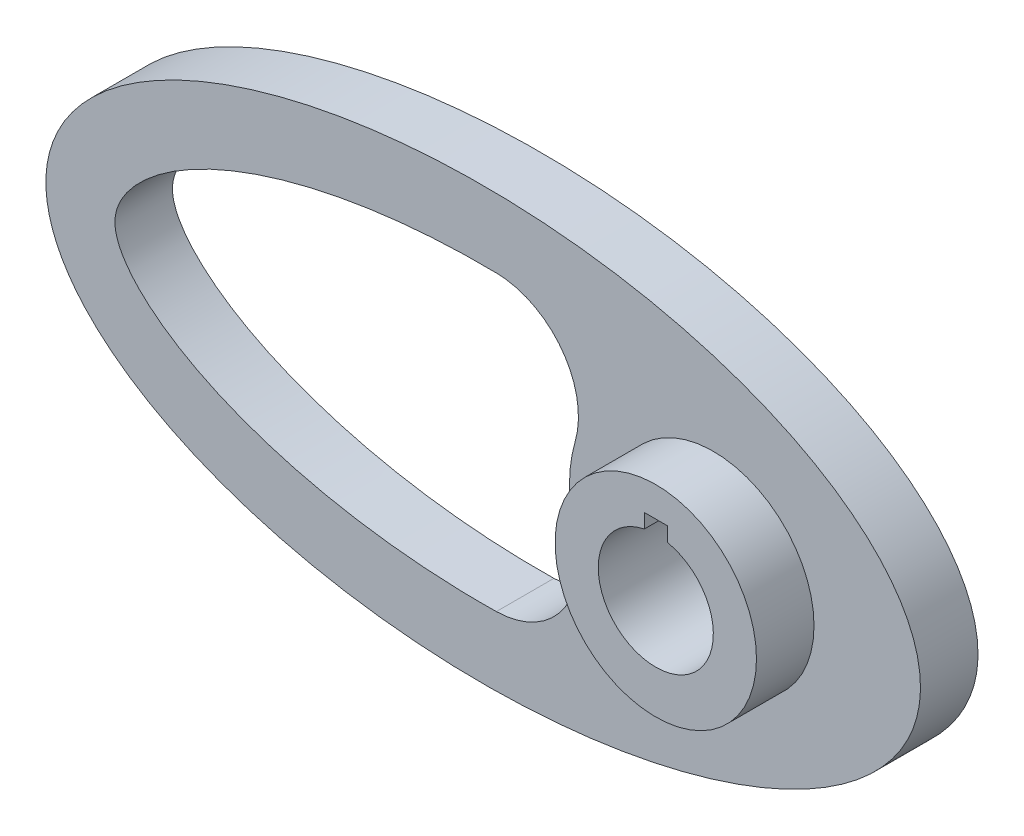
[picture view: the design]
ISO-10303-21;
HEADER;
FILE_DESCRIPTION(('STEP AP214'),'2;1');
FILE_NAME('part.step','',(''),(''),'','','');
FILE_SCHEMA(('AUTOMOTIVE_DESIGN { 1 0 10303 214 1 1 1 1 }'));
ENDSEC;
DATA;
#1=APPLICATION_CONTEXT('core data for automotive mechanical design processes');
#2=APPLICATION_PROTOCOL_DEFINITION('international standard','automotive_design',2000,#1);
#3=PRODUCT_CONTEXT('',#1,'mechanical');
#4=PRODUCT('Part','Part','',(#3));
#5=PRODUCT_RELATED_PRODUCT_CATEGORY('part','',(#4));
#6=PRODUCT_DEFINITION_FORMATION('','',#4);
#7=PRODUCT_DEFINITION_CONTEXT('part definition',#1,'design');
#8=PRODUCT_DEFINITION('design','',#6,#7);
#9=PRODUCT_DEFINITION_SHAPE('','',#8);
#10=(LENGTH_UNIT() NAMED_UNIT(*) SI_UNIT(.MILLI.,.METRE.));
#11=(NAMED_UNIT(*) PLANE_ANGLE_UNIT() SI_UNIT($,.RADIAN.));
#12=(NAMED_UNIT(*) SI_UNIT($,.STERADIAN.) SOLID_ANGLE_UNIT());
#13=UNCERTAINTY_MEASURE_WITH_UNIT(LENGTH_MEASURE(1.E-05),#10,'distance_accuracy_value','');
#14=(GEOMETRIC_REPRESENTATION_CONTEXT(3) GLOBAL_UNCERTAINTY_ASSIGNED_CONTEXT((#13)) GLOBAL_UNIT_ASSIGNED_CONTEXT((#10,
#11,#12)) REPRESENTATION_CONTEXT('',''));
#15=CARTESIAN_POINT('',(0.,0.,0.));
#16=DIRECTION('',(0.,0.,1.));
#17=DIRECTION('',(1.,0.,0.));
#18=AXIS2_PLACEMENT_3D('',#15,#16,#17);
#19=CARTESIAN_POINT('',(0.,0.,10.));
#20=DIRECTION('',(0.,0.,1.));
#21=DIRECTION('',(1.,0.,0.));
#22=AXIS2_PLACEMENT_3D('',#19,#20,#21);
#23=PLANE('',#22);
#24=CARTESIAN_POINT('',(2.29138758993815,25.4815579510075,10.));
#25=CARTESIAN_POINT('',(1.04978490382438,25.5014988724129,10.));
#26=CARTESIAN_POINT('',(-0.192085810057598,25.5052866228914,10.));
#27=CARTESIAN_POINT('',(-2.67421151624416,25.480297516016,10.));
#28=CARTESIAN_POINT('',(-3.9144668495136,25.4515543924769,10.));
#29=CARTESIAN_POINT('',(-6.39335454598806,25.3613033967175,10.));
#30=CARTESIAN_POINT('',(-7.63198732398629,25.2998069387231,10.));
#31=CARTESIAN_POINT('',(-10.1076273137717,25.143877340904,10.));
#32=CARTESIAN_POINT('',(-11.3446337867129,25.0494324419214,10.));
#33=CARTESIAN_POINT('',(-13.8169750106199,24.8266097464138,10.));
#34=CARTESIAN_POINT('',(-15.05230639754,24.6981945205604,10.));
#35=CARTESIAN_POINT('',(-17.521265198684,24.4065386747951,10.));
#36=CARTESIAN_POINT('',(-18.7548847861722,24.2432316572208,10.));
#37=CARTESIAN_POINT('',(-21.2203615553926,23.8802458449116,10.));
#38=CARTESIAN_POINT('',(-22.4522037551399,23.6804649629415,10.));
#39=CARTESIAN_POINT('',(-24.9140463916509,23.2423508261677,10.));
#40=CARTESIAN_POINT('',(-26.1440203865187,23.0038685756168,10.));
#41=CARTESIAN_POINT('',(-28.6014017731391,22.4860832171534,10.));
#42=CARTESIAN_POINT('',(-29.8287700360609,22.2065938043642,10.));
#43=CARTESIAN_POINT('',(-32.2730954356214,21.6051248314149,10.));
#44=CARTESIAN_POINT('',(-33.4900525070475,21.2831450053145,10.));
#45=CARTESIAN_POINT('',(-35.9103508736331,20.5939890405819,10.));
#46=CARTESIAN_POINT('',(-37.1137000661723,20.226840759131,10.));
#47=CARTESIAN_POINT('',(-39.5055771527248,19.4430324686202,10.));
#48=CARTESIAN_POINT('',(-40.6940886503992,19.0263222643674,10.));
#49=CARTESIAN_POINT('',(-43.0502715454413,18.1392862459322,10.));
#50=CARTESIAN_POINT('',(-44.217955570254,17.6689942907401,10.));
#51=CARTESIAN_POINT('',(-45.9481669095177,16.9194711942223,10.));
#52=CARTESIAN_POINT('',(-46.5204844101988,16.6627128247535,10.));
#53=CARTESIAN_POINT('',(-47.6569294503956,16.1336675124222,10.));
#54=CARTESIAN_POINT('',(-48.2210674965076,15.8614032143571,10.));
#55=CARTESIAN_POINT('',(-49.3406149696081,15.3003535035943,10.));
#56=CARTESIAN_POINT('',(-49.8960299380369,15.0115791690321,10.));
#57=CARTESIAN_POINT('',(-50.9972040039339,14.4157350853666,10.));
#58=CARTESIAN_POINT('',(-51.542960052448,14.1086596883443,10.));
#59=CARTESIAN_POINT('',(-52.6240771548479,13.47466429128,10.));
#60=CARTESIAN_POINT('',(-53.1594193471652,13.147712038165,10.));
#61=CARTESIAN_POINT('',(-54.2183300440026,12.4713832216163,10.));
#62=CARTESIAN_POINT('',(-54.7418527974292,12.12193480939,10.));
#63=CARTESIAN_POINT('',(-55.7749364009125,11.3976938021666,10.));
#64=CARTESIAN_POINT('',(-56.2844178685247,11.0227872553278,10.));
#65=CARTESIAN_POINT('',(-57.0337582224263,10.4412930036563,10.));
#66=CARTESIAN_POINT('',(-57.281068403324,10.2442635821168,10.));
#67=CARTESIAN_POINT('',(-57.7697192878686,9.84342837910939,10.));
#68=CARTESIAN_POINT('',(-58.0110660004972,9.63962994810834,10.));
#69=CARTESIAN_POINT('',(-58.4872732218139,9.22468734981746,10.));
#70=CARTESIAN_POINT('',(-58.7221351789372,9.01354484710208,10.));
#71=CARTESIAN_POINT('',(-59.184837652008,8.58330701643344,10.));
#72=CARTESIAN_POINT('',(-59.4126721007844,8.36420515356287,10.));
#73=CARTESIAN_POINT('',(-59.8606924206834,7.91760012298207,10.));
#74=CARTESIAN_POINT('',(-60.080865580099,7.6900841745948,10.));
#75=CARTESIAN_POINT('',(-60.5115641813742,7.22649144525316,10.));
#76=CARTESIAN_POINT('',(-60.7220991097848,6.99042351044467,10.));
#77=CARTESIAN_POINT('',(-61.1313808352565,6.50996293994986,10.));
#78=CARTESIAN_POINT('',(-61.3301732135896,6.26560921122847,10.));
#79=CARTESIAN_POINT('',(-61.7145817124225,5.76789181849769,10.));
#80=CARTESIAN_POINT('',(-61.9002371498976,5.51455876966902,10.));
#81=CARTESIAN_POINT('',(-62.1672003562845,5.12670200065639,10.));
#82=CARTESIAN_POINT('',(-62.2542597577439,4.9961206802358,10.));
#83=CARTESIAN_POINT('',(-62.4242991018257,4.73213028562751,10.));
#84=CARTESIAN_POINT('',(-62.5072747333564,4.59871842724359,10.));
#85=CARTESIAN_POINT('',(-62.6688983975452,4.32889217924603,10.));
#86=CARTESIAN_POINT('',(-62.7475364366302,4.1924717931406,10.));
#87=CARTESIAN_POINT('',(-62.8999829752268,3.91627986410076,10.));
#88=CARTESIAN_POINT('',(-62.9737721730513,3.77649763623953,10.));
#89=CARTESIAN_POINT('',(-63.116028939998,3.49327587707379,10.));
#90=CARTESIAN_POINT('',(-63.1844648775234,3.34982041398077,10.));
#91=CARTESIAN_POINT('',(-63.3150602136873,3.05961797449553,10.));
#92=CARTESIAN_POINT('',(-63.3772027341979,2.91286337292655,10.));
#93=CARTESIAN_POINT('',(-63.4940909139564,2.61689388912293,10.));
#94=CARTESIAN_POINT('',(-63.5488564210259,2.46768687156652,10.));
#95=CARTESIAN_POINT('',(-63.6500699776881,2.16719850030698,10.));
#96=CARTESIAN_POINT('',(-63.6965543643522,2.01592951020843,10.));
#97=CARTESIAN_POINT('',(-63.7595502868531,1.78723887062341,10.));
#98=CARTESIAN_POINT('',(-63.779422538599,1.7107324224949,10.));
#99=CARTESIAN_POINT('',(-63.8168217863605,1.55708383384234,10.));
#100=CARTESIAN_POINT('',(-63.8343469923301,1.4799412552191,10.));
#101=CARTESIAN_POINT('',(-63.8669622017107,1.32499797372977,10.));
#102=CARTESIAN_POINT('',(-63.8820477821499,1.24719633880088,10.));
#103=CARTESIAN_POINT('',(-63.9096542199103,1.09086592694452,10.));
#104=CARTESIAN_POINT('',(-63.9221662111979,1.01233557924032,10.));
#105=CARTESIAN_POINT('',(-63.9445061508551,0.854592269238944,10.));
#106=CARTESIAN_POINT('',(-63.9543238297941,0.775377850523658,10.));
#107=CARTESIAN_POINT('',(-63.9711939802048,0.616427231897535,10.));
#108=CARTESIAN_POINT('',(-63.9782385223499,0.536690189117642,10.));
#109=CARTESIAN_POINT('',(-63.9894676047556,0.376852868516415,10.));
#110=CARTESIAN_POINT('',(-63.9936463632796,0.296752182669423,10.));
#111=CARTESIAN_POINT('',(-63.9990398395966,0.136349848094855,10.));
#112=CARTESIAN_POINT('',(-64.0002508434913,0.056048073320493,10.));
#113=CARTESIAN_POINT('',(-63.9996591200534,-0.104258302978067,10.));
#114=CARTESIAN_POINT('',(-63.9978671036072,-0.184262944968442,10.));
#115=CARTESIAN_POINT('',(-63.9913669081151,-0.34371225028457,10.));
#116=CARTESIAN_POINT('',(-63.9866748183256,-0.423157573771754,10.));
#117=CARTESIAN_POINT('',(-63.9744623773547,-0.58150500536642,10.));
#118=CARTESIAN_POINT('',(-63.9669536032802,-0.66040800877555,10.));
#119=CARTESIAN_POINT('',(-63.9492030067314,-0.817687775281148,10.));
#120=CARTESIAN_POINT('',(-63.9389686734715,-0.896065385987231,10.));
#121=CARTESIAN_POINT('',(-63.9158596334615,-1.0523117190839,10.));
#122=CARTESIAN_POINT('',(-63.9029888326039,-1.13018102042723,10.));
#123=CARTESIAN_POINT('',(-63.8746995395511,-1.28542803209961,10.));
#124=CARTESIAN_POINT('',(-63.8592818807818,-1.36280589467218,10.));
#125=CARTESIAN_POINT('',(-63.8259909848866,-1.51708844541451,10.));
#126=CARTESIAN_POINT('',(-63.8081160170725,-1.59399275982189,10.));
#127=CARTESIAN_POINT('',(-63.7700017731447,-1.74734310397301,10.));
#128=CARTESIAN_POINT('',(-63.7497586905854,-1.82378818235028,10.));
#129=CARTESIAN_POINT('',(-63.6855341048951,-2.05278927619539,10.));
#130=CARTESIAN_POINT('',(-63.638188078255,-2.20441241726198,10.));
#131=CARTESIAN_POINT('',(-63.5352735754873,-2.50550964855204,10.));
#132=CARTESIAN_POINT('',(-63.4796721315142,-2.65497235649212,10.));
#133=CARTESIAN_POINT('',(-63.3614065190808,-2.95077731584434,10.));
#134=CARTESIAN_POINT('',(-63.2987543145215,-3.09712436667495,10.));
#135=CARTESIAN_POINT('',(-63.1674154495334,-3.38606146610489,10.));
#136=CARTESIAN_POINT('',(-63.0987654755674,-3.52866825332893,10.));
#137=CARTESIAN_POINT('',(-62.9559589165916,-3.81065076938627,10.));
#138=CARTESIAN_POINT('',(-62.8818162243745,-3.95003355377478,10.));
#139=CARTESIAN_POINT('',(-62.7284937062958,-4.22587880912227,10.));
#140=CARTESIAN_POINT('',(-62.6493170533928,-4.36234304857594,10.));
#141=CARTESIAN_POINT('',(-62.486326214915,-4.63270229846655,10.));
#142=CARTESIAN_POINT('',(-62.4025063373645,-4.76659387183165,10.));
#143=CARTESIAN_POINT('',(-62.2305404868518,-5.03188349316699,10.));
#144=CARTESIAN_POINT('',(-62.1423874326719,-5.16327693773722,10.));
#145=CARTESIAN_POINT('',(-61.8717676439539,-5.55405998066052,10.));
#146=CARTESIAN_POINT('',(-61.6835050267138,-5.80945293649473,10.));
#147=CARTESIAN_POINT('',(-61.2944050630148,-6.31029008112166,10.));
#148=CARTESIAN_POINT('',(-61.0935708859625,-6.55573675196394,10.));
#149=CARTESIAN_POINT('',(-60.6820021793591,-7.03606317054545,10.));
#150=CARTESIAN_POINT('',(-60.4713215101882,-7.27098916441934,10.));
#151=CARTESIAN_POINT('',(-60.0412969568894,-7.73146271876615,10.));
#152=CARTESIAN_POINT('',(-59.8219800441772,-7.95703556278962,10.));
#153=CARTESIAN_POINT('',(-59.3757691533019,-8.39998626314,10.));
#154=CARTESIAN_POINT('',(-59.1488847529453,-8.61737378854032,10.));
#155=CARTESIAN_POINT('',(-58.6880019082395,-9.04446913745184,10.));
#156=CARTESIAN_POINT('',(-58.4540033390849,-9.25417682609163,10.));
#157=CARTESIAN_POINT('',(-57.9794431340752,-9.66650734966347,10.));
#158=CARTESIAN_POINT('',(-57.7388751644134,-9.86912288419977,10.));
#159=CARTESIAN_POINT('',(-57.251702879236,-10.2678266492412,10.));
#160=CARTESIAN_POINT('',(-57.0050887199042,-10.4639028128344,10.));
#161=CARTESIAN_POINT('',(-56.2563632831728,-11.043723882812,10.));
#162=CARTESIAN_POINT('',(-55.7467734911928,-11.4178538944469,10.));
#163=CARTESIAN_POINT('',(-54.7125360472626,-12.14151850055,10.));
#164=CARTESIAN_POINT('',(-54.1879318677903,-12.4911156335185,10.));
#165=CARTESIAN_POINT('',(-53.1275181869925,-13.1673545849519,10.));
#166=CARTESIAN_POINT('',(-52.5917704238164,-13.4940934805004,10.));
#167=CARTESIAN_POINT('',(-51.5102632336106,-14.12732975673,10.));
#168=CARTESIAN_POINT('',(-50.9645320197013,-14.4338754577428,10.));
#169=CARTESIAN_POINT('',(-49.8639103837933,-15.0284782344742,10.));
#170=CARTESIAN_POINT('',(-49.3090310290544,-15.3165558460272,10.));
#171=CARTESIAN_POINT('',(-48.1910198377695,-15.8760647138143,10.));
#172=CARTESIAN_POINT('',(-47.6278887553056,-16.1474974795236,10.));
#173=CARTESIAN_POINT('',(-46.4939032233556,-16.6747651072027,10.));
#174=CARTESIAN_POINT('',(-45.9230435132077,-16.9305886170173,10.));
#175=CARTESIAN_POINT('',(-44.198264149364,-17.6770382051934,10.));
#176=CARTESIAN_POINT('',(-43.0346543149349,-18.1454000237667,10.));
#177=CARTESIAN_POINT('',(-40.683844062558,-19.0300199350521,10.));
#178=CARTESIAN_POINT('',(-39.4965815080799,-19.4461113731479,10.));
#179=CARTESIAN_POINT('',(-37.110977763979,-20.2275956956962,10.));
#180=CARTESIAN_POINT('',(-35.912702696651,-20.5931911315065,10.));
#181=CARTESIAN_POINT('',(-33.5083440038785,-21.2781613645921,10.));
#182=CARTESIAN_POINT('',(-32.3023120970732,-21.597718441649,10.));
#183=CARTESIAN_POINT('',(-29.8828770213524,-22.1940182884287,10.));
#184=CARTESIAN_POINT('',(-28.6694991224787,-22.4708639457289,10.));
#185=CARTESIAN_POINT('',(-26.2360011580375,-22.9853181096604,10.));
#186=CARTESIAN_POINT('',(-25.0158909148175,-23.2229732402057,10.));
#187=CARTESIAN_POINT('',(-22.5691982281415,-23.6607598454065,10.));
#188=CARTESIAN_POINT('',(-21.3426169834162,-23.8608980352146,10.));
#189=CARTESIAN_POINT('',(-18.8833020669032,-24.2255117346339,10.));
#190=CARTESIAN_POINT('',(-17.6505646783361,-24.3899620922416,10.));
#191=CARTESIAN_POINT('',(-15.1791276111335,-24.6843887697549,10.));
#192=CARTESIAN_POINT('',(-13.9404217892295,-24.8143134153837,10.));
#193=CARTESIAN_POINT('',(-11.4571604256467,-25.0403422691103,10.));
#194=CARTESIAN_POINT('',(-10.2125980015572,-25.136370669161,10.));
#195=CARTESIAN_POINT('',(-7.717714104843,-25.2952354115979,10.));
#196=CARTESIAN_POINT('',(-6.46738642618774,-25.3579740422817,10.));
#197=CARTESIAN_POINT('',(-3.96385101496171,-25.4502131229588,10.));
#198=CARTESIAN_POINT('',(-2.71064166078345,-25.4796694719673,10.));
#199=CARTESIAN_POINT('',(-0.207728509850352,-25.505338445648,10.));
#200=CARTESIAN_POINT('',(1.04197424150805,-25.5016528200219,10.));
#201=CARTESIAN_POINT('',(2.29140733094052,-25.4815575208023,10.));
#202=B_SPLINE_CURVE_WITH_KNOTS('',3,(#24,#25,#26,#27,#28,#29,#30,#31,#32,#33,#34,#35,#36,#37,
#38,#39,#40,#41,#42,#43,#44,#45,#46,#47,#48,#49,#50,#51,#52,#53,#54,#55,#56,#57,#58,#59,#60,#61,
#62,#63,#64,#65,#66,#67,#68,#69,#70,#71,#72,#73,#74,#75,#76,#77,#78,#79,#80,#81,#82,#83,#84,#85,
#86,#87,#88,#89,#90,#91,#92,#93,#94,#95,#96,#97,#98,#99,#100,#101,#102,#103,#104,#105,#106,#107,
#108,#109,#110,#111,#112,#113,#114,#115,#116,#117,#118,#119,#120,#121,#122,#123,#124,#125,#126,
#127,#128,#129,#130,#131,#132,#133,#134,#135,#136,#137,#138,#139,#140,#141,#142,#143,#144,#145,
#146,#147,#148,#149,#150,#151,#152,#153,#154,#155,#156,#157,#158,#159,#160,#161,#162,#163,#164,
#165,#166,#167,#168,#169,#170,#171,#172,#173,#174,#175,#176,#177,#178,#179,#180,#181,#182,#183,
#184,#185,#186,#187,#188,#189,#190,#191,#192,#193,#194,#195,#196,#197,#198,#199,#200,#201),
.UNSPECIFIED.,.F.,.F.,(4,2,2,2,2,2,2,2,2,2,2,2,2,2,2,2,2,2,2,2,2,2,2,2,2,2,2,2,2,2,2,2,2,2,2,2,
2,2,2,2,2,2,2,2,2,2,2,2,2,2,2,2,2,2,2,2,2,2,2,2,2,2,2,2,2,2,2,2,2,2,2,2,2,2,2,2,2,2,2,2,2,2,2,2,
2,2,2,2,4),(0.,3.72519639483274,7.44653337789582,11.1665743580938,14.8879443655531,
18.6134318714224,22.3460729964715,26.0893262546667,29.8473482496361,33.6230051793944,
37.3986857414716,41.1720492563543,44.9492674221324,48.724111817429,50.6057334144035,
52.4846742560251,54.3623688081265,56.2406458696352,58.1220565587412,60.0098068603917,
61.9066485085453,62.8551513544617,63.8026558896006,64.7499470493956,65.6980343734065,
66.6476262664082,67.5962624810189,68.5409347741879,69.4826484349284,69.9534086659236,
70.4246556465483,70.8969465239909,71.3710159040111,71.8477027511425,72.3256359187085,
72.802256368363,73.2767309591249,73.5138358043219,73.751120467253,73.988830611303,
74.2273464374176,74.4667591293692,74.7068514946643,74.9474268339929,75.188303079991,
75.4283220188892,75.6670211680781,75.9047497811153,76.1418317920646,76.3785650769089,
76.6152210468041,76.8520445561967,77.0892540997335,77.5655088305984,78.0437193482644,
78.5211303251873,78.9958020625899,79.4693117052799,79.9425257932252,80.4163333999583,
80.8909428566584,81.8422630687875,82.7933444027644,83.7397232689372,84.6833503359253,
85.6258253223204,86.5683168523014,87.5117516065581,88.4568404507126,90.3525676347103,
92.2432721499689,94.1253865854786,96.0028201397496,97.8781284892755,99.7532665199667,
101.629752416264,105.391116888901,109.164184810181,112.921648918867,116.663801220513,
120.396793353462,124.125311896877,127.853162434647,131.583631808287,135.319653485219,
139.063978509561,142.819233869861,146.57945935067,150.328144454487),.UNSPECIFIED.);
#203=CARTESIAN_POINT('',(2.29138758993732,25.4815579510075,10.));
#204=VERTEX_POINT('',#203);
#205=CARTESIAN_POINT('',(2.29140733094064,-25.4815575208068,10.));
#206=VERTEX_POINT('',#205);
#207=EDGE_CURVE('E143',#204,#206,#202,.T.);
#208=ORIENTED_EDGE('',*,*,#207,.F.);
#209=CARTESIAN_POINT('',(2.05775390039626,10.9834403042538,10.));
#210=DIRECTION('',(0.,0.,1.));
#211=DIRECTION('',(1.,0.,0.));
#212=AXIS2_PLACEMENT_3D('',#209,#210,#211);
#213=CIRCLE('',#212,14.5);
#214=CARTESIAN_POINT('',(15.9859201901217,6.95154449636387,10.));
#215=VERTEX_POINT('',#214);
#216=EDGE_CURVE('E178',#215,#204,#213,.T.);
#217=ORIENTED_EDGE('',*,*,#216,.F.);
#218=CARTESIAN_POINT('',(40.,0.,10.));
#219=DIRECTION('',(0.,0.,-1.));
#220=DIRECTION('',(1.,0.,0.));
#221=AXIS2_PLACEMENT_3D('',#218,#219,#220);
#222=CIRCLE('',#221,25.0000000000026);
#223=CARTESIAN_POINT('',(15.9859201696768,-6.95154442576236,10.));
#224=VERTEX_POINT('',#223);
#225=EDGE_CURVE('E190',#224,#215,#222,.T.);
#226=ORIENTED_EDGE('',*,*,#225,.F.);
#227=CARTESIAN_POINT('',(2.05775386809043,-10.9834401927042,10.));
#228=DIRECTION('',(0.,0.,1.));
#229=DIRECTION('',(1.,0.,0.));
#230=AXIS2_PLACEMENT_3D('',#227,#228,#229);
#231=CIRCLE('',#230,14.5000000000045);
#232=EDGE_CURVE('E188',#206,#224,#231,.T.);
#233=ORIENTED_EDGE('',*,*,#232,.F.);
#234=EDGE_LOOP('',(#208,#217,#226,#233));
#235=FACE_BOUND('',#234,.T.);
#236=CARTESIAN_POINT('',(0.,0.,10.));
#237=DIRECTION('',(0.,0.,1.));
#238=DIRECTION('',(1.,0.,0.));
#239=AXIS2_PLACEMENT_3D('',#236,#237,#238);
#240=ELLIPSE('',#239,76.,37.5);
#241=CARTESIAN_POINT('',(76.,0.,10.));
#242=VERTEX_POINT('',#241);
#243=EDGE_CURVE('E11',#242,#242,#240,.T.);
#244=ORIENTED_EDGE('',*,*,#243,.T.);
#245=EDGE_LOOP('',(#244));
#246=FACE_BOUND('',#245,.T.);
#247=CARTESIAN_POINT('',(40.,0.,10.));
#248=DIRECTION('',(0.,0.,1.));
#249=DIRECTION('',(1.,0.,0.));
#250=AXIS2_PLACEMENT_3D('',#247,#248,#249);
#251=CIRCLE('',#250,17.5);
#252=CARTESIAN_POINT('',(57.5,0.,10.));
#253=VERTEX_POINT('',#252);
#254=EDGE_CURVE('E200',#253,#253,#251,.T.);
#255=ORIENTED_EDGE('',*,*,#254,.F.);
#256=EDGE_LOOP('',(#255));
#257=FACE_BOUND('',#256,.T.);
#258=ADVANCED_FACE('F39',(#235,#246,#257),#23,.T.);
#259=DIRECTION('',(0.,0.,-1.));
#260=VECTOR('',#259,1.);
#261=SURFACE_OF_LINEAR_EXTRUSION('',#240,#260);
#262=ORIENTED_EDGE('',*,*,#243,.F.);
#263=EDGE_LOOP('',(#262));
#264=FACE_BOUND('',#263,.T.);
#265=CARTESIAN_POINT('',(0.,0.,0.));
#266=DIRECTION('',(0.,0.,1.));
#267=DIRECTION('',(1.,0.,0.));
#268=AXIS2_PLACEMENT_3D('',#265,#266,#267);
#269=ELLIPSE('',#268,76.,37.5);
#270=CARTESIAN_POINT('',(76.,0.,0.));
#271=VERTEX_POINT('',#270);
#272=EDGE_CURVE('E51',#271,#271,#269,.T.);
#273=ORIENTED_EDGE('',*,*,#272,.T.);
#274=EDGE_LOOP('',(#273));
#275=FACE_BOUND('',#274,.T.);
#276=ADVANCED_FACE('F41',(#264,#275),#261,.F.);
#277=CARTESIAN_POINT('',(0.,0.,0.));
#278=DIRECTION('',(0.,0.,1.));
#279=DIRECTION('',(1.,0.,0.));
#280=AXIS2_PLACEMENT_3D('',#277,#278,#279);
#281=PLANE('',#280);
#282=DIRECTION('',(0.,-1.,0.));
#283=VECTOR('',#282,1.);
#284=CARTESIAN_POINT('',(38.,0.,0.));
#285=LINE('',#284,#283);
#286=CARTESIAN_POINT('',(38.,12.2979589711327,0.));
#287=VERTEX_POINT('',#286);
#288=CARTESIAN_POINT('',(38.,9.79795897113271,0.));
#289=VERTEX_POINT('',#288);
#290=EDGE_CURVE('E136',#287,#289,#285,.T.);
#291=ORIENTED_EDGE('',*,*,#290,.T.);
#292=CARTESIAN_POINT('',(40.,0.,0.));
#293=DIRECTION('',(0.,0.,1.));
#294=DIRECTION('',(1.,0.,0.));
#295=AXIS2_PLACEMENT_3D('',#292,#293,#294);
#296=CIRCLE('',#295,10.);
#297=CARTESIAN_POINT('',(42.,9.79795897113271,0.));
#298=VERTEX_POINT('',#297);
#299=EDGE_CURVE('E145',#289,#298,#296,.T.);
#300=ORIENTED_EDGE('',*,*,#299,.T.);
#301=DIRECTION('',(0.,1.,0.));
#302=VECTOR('',#301,1.);
#303=CARTESIAN_POINT('',(42.,0.,0.));
#304=LINE('',#303,#302);
#305=CARTESIAN_POINT('',(42.,12.2979589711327,0.));
#306=VERTEX_POINT('',#305);
#307=EDGE_CURVE('E133',#298,#306,#304,.T.);
#308=ORIENTED_EDGE('',*,*,#307,.T.);
#309=DIRECTION('',(-1.,0.,0.));
#310=VECTOR('',#309,1.);
#311=CARTESIAN_POINT('',(0.,12.2979589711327,0.));
#312=LINE('',#311,#310);
#313=EDGE_CURVE('E112',#306,#287,#312,.T.);
#314=ORIENTED_EDGE('',*,*,#313,.T.);
#315=EDGE_LOOP('',(#291,#300,#308,#314));
#316=FACE_BOUND('',#315,.T.);
#317=CARTESIAN_POINT('',(2.05775390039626,10.9834403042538,0.));
#318=DIRECTION('',(0.,0.,1.));
#319=DIRECTION('',(1.,0.,0.));
#320=AXIS2_PLACEMENT_3D('',#317,#318,#319);
#321=CIRCLE('',#320,14.5);
#322=CARTESIAN_POINT('',(15.9859201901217,6.95154449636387,0.));
#323=VERTEX_POINT('',#322);
#324=CARTESIAN_POINT('',(2.29138758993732,25.4815579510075,0.));
#325=VERTEX_POINT('',#324);
#326=EDGE_CURVE('E293',#323,#325,#321,.T.);
#327=ORIENTED_EDGE('',*,*,#326,.T.);
#328=CARTESIAN_POINT('',(2.29140733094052,-25.4815575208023,0.));
#329=CARTESIAN_POINT('',(1.04197424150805,-25.5016528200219,0.));
#330=CARTESIAN_POINT('',(-0.207728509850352,-25.505338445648,0.));
#331=CARTESIAN_POINT('',(-2.71064166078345,-25.4796694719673,0.));
#332=CARTESIAN_POINT('',(-3.96385101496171,-25.4502131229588,0.));
#333=CARTESIAN_POINT('',(-6.46738642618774,-25.3579740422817,0.));
#334=CARTESIAN_POINT('',(-7.717714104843,-25.2952354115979,0.));
#335=CARTESIAN_POINT('',(-10.2125980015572,-25.136370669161,0.));
#336=CARTESIAN_POINT('',(-11.4571604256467,-25.0403422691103,0.));
#337=CARTESIAN_POINT('',(-13.9404217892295,-24.8143134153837,0.));
#338=CARTESIAN_POINT('',(-15.1791276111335,-24.6843887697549,0.));
#339=CARTESIAN_POINT('',(-17.6505646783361,-24.3899620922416,0.));
#340=CARTESIAN_POINT('',(-18.8833020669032,-24.2255117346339,0.));
#341=CARTESIAN_POINT('',(-21.3426169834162,-23.8608980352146,0.));
#342=CARTESIAN_POINT('',(-22.5691982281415,-23.6607598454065,0.));
#343=CARTESIAN_POINT('',(-25.0158909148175,-23.2229732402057,0.));
#344=CARTESIAN_POINT('',(-26.2360011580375,-22.9853181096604,0.));
#345=CARTESIAN_POINT('',(-28.6694991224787,-22.4708639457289,0.));
#346=CARTESIAN_POINT('',(-29.8828770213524,-22.1940182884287,0.));
#347=CARTESIAN_POINT('',(-32.3023120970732,-21.597718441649,0.));
#348=CARTESIAN_POINT('',(-33.5083440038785,-21.2781613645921,0.));
#349=CARTESIAN_POINT('',(-35.912702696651,-20.5931911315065,0.));
#350=CARTESIAN_POINT('',(-37.110977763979,-20.2275956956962,0.));
#351=CARTESIAN_POINT('',(-39.4965815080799,-19.4461113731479,0.));
#352=CARTESIAN_POINT('',(-40.683844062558,-19.0300199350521,0.));
#353=CARTESIAN_POINT('',(-43.0346543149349,-18.1454000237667,0.));
#354=CARTESIAN_POINT('',(-44.198264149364,-17.6770382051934,0.));
#355=CARTESIAN_POINT('',(-45.9230435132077,-16.9305886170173,0.));
#356=CARTESIAN_POINT('',(-46.4939032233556,-16.6747651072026,0.));
#357=CARTESIAN_POINT('',(-47.6278887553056,-16.1474974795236,0.));
#358=CARTESIAN_POINT('',(-48.1910198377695,-15.8760647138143,0.));
#359=CARTESIAN_POINT('',(-49.3090310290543,-15.3165558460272,0.));
#360=CARTESIAN_POINT('',(-49.8639103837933,-15.0284782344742,0.));
#361=CARTESIAN_POINT('',(-50.9645320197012,-14.4338754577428,0.));
#362=CARTESIAN_POINT('',(-51.5102632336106,-14.12732975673,0.));
#363=CARTESIAN_POINT('',(-52.5917704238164,-13.4940934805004,0.));
#364=CARTESIAN_POINT('',(-53.1275181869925,-13.1673545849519,0.));
#365=CARTESIAN_POINT('',(-54.1879318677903,-12.4911156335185,0.));
#366=CARTESIAN_POINT('',(-54.7125360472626,-12.14151850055,0.));
#367=CARTESIAN_POINT('',(-55.7467734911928,-11.4178538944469,0.));
#368=CARTESIAN_POINT('',(-56.2563632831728,-11.043723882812,0.));
#369=CARTESIAN_POINT('',(-57.0050887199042,-10.4639028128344,0.));
#370=CARTESIAN_POINT('',(-57.251702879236,-10.2678266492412,0.));
#371=CARTESIAN_POINT('',(-57.7388751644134,-9.86912288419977,0.));
#372=CARTESIAN_POINT('',(-57.9794431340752,-9.66650734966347,0.));
#373=CARTESIAN_POINT('',(-58.4540033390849,-9.25417682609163,0.));
#374=CARTESIAN_POINT('',(-58.6880019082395,-9.04446913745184,0.));
#375=CARTESIAN_POINT('',(-59.1488847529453,-8.61737378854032,0.));
#376=CARTESIAN_POINT('',(-59.3757691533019,-8.39998626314,0.));
#377=CARTESIAN_POINT('',(-59.8219800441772,-7.95703556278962,0.));
#378=CARTESIAN_POINT('',(-60.0412969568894,-7.73146271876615,0.));
#379=CARTESIAN_POINT('',(-60.4713215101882,-7.27098916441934,0.));
#380=CARTESIAN_POINT('',(-60.6820021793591,-7.03606317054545,0.));
#381=CARTESIAN_POINT('',(-61.0935708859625,-6.55573675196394,0.));
#382=CARTESIAN_POINT('',(-61.2944050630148,-6.31029008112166,0.));
#383=CARTESIAN_POINT('',(-61.6835050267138,-5.80945293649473,0.));
#384=CARTESIAN_POINT('',(-61.8717676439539,-5.55405998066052,0.));
#385=CARTESIAN_POINT('',(-62.1423874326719,-5.16327693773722,0.));
#386=CARTESIAN_POINT('',(-62.2305404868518,-5.03188349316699,0.));
#387=CARTESIAN_POINT('',(-62.4025063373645,-4.76659387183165,0.));
#388=CARTESIAN_POINT('',(-62.486326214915,-4.63270229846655,0.));
#389=CARTESIAN_POINT('',(-62.6493170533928,-4.36234304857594,0.));
#390=CARTESIAN_POINT('',(-62.7284937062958,-4.22587880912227,0.));
#391=CARTESIAN_POINT('',(-62.8818162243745,-3.95003355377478,0.));
#392=CARTESIAN_POINT('',(-62.9559589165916,-3.81065076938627,0.));
#393=CARTESIAN_POINT('',(-63.0987654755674,-3.52866825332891,0.));
#394=CARTESIAN_POINT('',(-63.1674154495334,-3.38606146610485,0.));
#395=CARTESIAN_POINT('',(-63.2987543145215,-3.09712436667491,0.));
#396=CARTESIAN_POINT('',(-63.3614065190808,-2.95077731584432,0.));
#397=CARTESIAN_POINT('',(-63.4796721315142,-2.65497235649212,0.));
#398=CARTESIAN_POINT('',(-63.5352735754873,-2.50550964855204,0.));
#399=CARTESIAN_POINT('',(-63.638188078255,-2.20441241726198,0.));
#400=CARTESIAN_POINT('',(-63.6855341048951,-2.05278927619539,0.));
#401=CARTESIAN_POINT('',(-63.7497586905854,-1.82378818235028,0.));
#402=CARTESIAN_POINT('',(-63.7700017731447,-1.74734310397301,0.));
#403=CARTESIAN_POINT('',(-63.8081160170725,-1.59399275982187,0.));
#404=CARTESIAN_POINT('',(-63.8259909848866,-1.51708844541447,0.));
#405=CARTESIAN_POINT('',(-63.8592818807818,-1.36280589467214,0.));
#406=CARTESIAN_POINT('',(-63.8746995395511,-1.28542803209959,0.));
#407=CARTESIAN_POINT('',(-63.9029888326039,-1.13018102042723,0.));
#408=CARTESIAN_POINT('',(-63.9158596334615,-1.0523117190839,0.));
#409=CARTESIAN_POINT('',(-63.9389686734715,-0.896065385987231,0.));
#410=CARTESIAN_POINT('',(-63.9492030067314,-0.817687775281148,0.));
#411=CARTESIAN_POINT('',(-63.9669536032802,-0.66040800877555,0.));
#412=CARTESIAN_POINT('',(-63.9744623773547,-0.58150500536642,0.));
#413=CARTESIAN_POINT('',(-63.9866748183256,-0.423157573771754,0.));
#414=CARTESIAN_POINT('',(-63.9913669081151,-0.34371225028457,0.));
#415=CARTESIAN_POINT('',(-63.9978671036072,-0.184262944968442,0.));
#416=CARTESIAN_POINT('',(-63.9996591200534,-0.104258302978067,0.));
#417=CARTESIAN_POINT('',(-64.0002508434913,0.056048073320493,0.));
#418=CARTESIAN_POINT('',(-63.9990398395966,0.136349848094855,0.));
#419=CARTESIAN_POINT('',(-63.9936463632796,0.296752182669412,0.));
#420=CARTESIAN_POINT('',(-63.9894676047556,0.376852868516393,0.));
#421=CARTESIAN_POINT('',(-63.9782385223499,0.53669018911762,0.));
#422=CARTESIAN_POINT('',(-63.9711939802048,0.616427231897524,0.));
#423=CARTESIAN_POINT('',(-63.9543238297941,0.775377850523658,0.));
#424=CARTESIAN_POINT('',(-63.9445061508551,0.854592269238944,0.));
#425=CARTESIAN_POINT('',(-63.9221662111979,1.01233557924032,0.));
#426=CARTESIAN_POINT('',(-63.9096542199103,1.09086592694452,0.));
#427=CARTESIAN_POINT('',(-63.8820477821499,1.24719633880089,0.));
#428=CARTESIAN_POINT('',(-63.8669622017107,1.32499797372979,0.));
#429=CARTESIAN_POINT('',(-63.8343469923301,1.47994125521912,0.));
#430=CARTESIAN_POINT('',(-63.8168217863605,1.55708383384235,0.));
#431=CARTESIAN_POINT('',(-63.779422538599,1.71073242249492,0.));
#432=CARTESIAN_POINT('',(-63.7595502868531,1.78723887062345,0.));
#433=CARTESIAN_POINT('',(-63.6965543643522,2.01592951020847,0.));
#434=CARTESIAN_POINT('',(-63.6500699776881,2.167198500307,0.));
#435=CARTESIAN_POINT('',(-63.5488564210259,2.46768687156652,0.));
#436=CARTESIAN_POINT('',(-63.4940909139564,2.61689388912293,0.));
#437=CARTESIAN_POINT('',(-63.3772027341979,2.91286337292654,0.));
#438=CARTESIAN_POINT('',(-63.3150602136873,3.05961797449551,0.));
#439=CARTESIAN_POINT('',(-63.1844648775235,3.34982041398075,0.));
#440=CARTESIAN_POINT('',(-63.116028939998,3.49327587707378,0.));
#441=CARTESIAN_POINT('',(-62.9737721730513,3.77649763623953,0.));
#442=CARTESIAN_POINT('',(-62.8999829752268,3.91627986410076,0.));
#443=CARTESIAN_POINT('',(-62.7475364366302,4.1924717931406,0.));
#444=CARTESIAN_POINT('',(-62.6688983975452,4.32889217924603,0.));
#445=CARTESIAN_POINT('',(-62.5072747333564,4.59871842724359,0.));
#446=CARTESIAN_POINT('',(-62.4242991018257,4.73213028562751,0.));
#447=CARTESIAN_POINT('',(-62.2542597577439,4.9961206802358,0.));
#448=CARTESIAN_POINT('',(-62.1672003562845,5.12670200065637,0.));
#449=CARTESIAN_POINT('',(-61.9002371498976,5.514558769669,0.));
#450=CARTESIAN_POINT('',(-61.7145817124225,5.76789181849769,0.));
#451=CARTESIAN_POINT('',(-61.3301732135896,6.26560921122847,0.));
#452=CARTESIAN_POINT('',(-61.1313808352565,6.50996293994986,0.));
#453=CARTESIAN_POINT('',(-60.7220991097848,6.99042351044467,0.));
#454=CARTESIAN_POINT('',(-60.5115641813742,7.22649144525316,0.));
#455=CARTESIAN_POINT('',(-60.080865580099,7.6900841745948,0.));
#456=CARTESIAN_POINT('',(-59.8606924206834,7.91760012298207,0.));
#457=CARTESIAN_POINT('',(-59.4126721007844,8.36420515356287,0.));
#458=CARTESIAN_POINT('',(-59.184837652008,8.58330701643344,0.));
#459=CARTESIAN_POINT('',(-58.7221351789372,9.01354484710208,0.));
#460=CARTESIAN_POINT('',(-58.4872732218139,9.22468734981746,0.));
#461=CARTESIAN_POINT('',(-58.0110660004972,9.63962994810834,0.));
#462=CARTESIAN_POINT('',(-57.7697192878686,9.84342837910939,0.));
#463=CARTESIAN_POINT('',(-57.281068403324,10.2442635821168,0.));
#464=CARTESIAN_POINT('',(-57.0337582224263,10.4412930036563,0.));
#465=CARTESIAN_POINT('',(-56.2844178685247,11.0227872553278,0.));
#466=CARTESIAN_POINT('',(-55.7749364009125,11.3976938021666,0.));
#467=CARTESIAN_POINT('',(-54.7418527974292,12.12193480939,0.));
#468=CARTESIAN_POINT('',(-54.2183300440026,12.4713832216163,0.));
#469=CARTESIAN_POINT('',(-53.1594193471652,13.147712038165,0.));
#470=CARTESIAN_POINT('',(-52.6240771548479,13.47466429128,0.));
#471=CARTESIAN_POINT('',(-51.542960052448,14.1086596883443,0.));
#472=CARTESIAN_POINT('',(-50.9972040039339,14.4157350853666,0.));
#473=CARTESIAN_POINT('',(-49.8960299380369,15.0115791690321,0.));
#474=CARTESIAN_POINT('',(-49.3406149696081,15.3003535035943,0.));
#475=CARTESIAN_POINT('',(-48.2210674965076,15.8614032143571,0.));
#476=CARTESIAN_POINT('',(-47.6569294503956,16.1336675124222,0.));
#477=CARTESIAN_POINT('',(-46.5204844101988,16.6627128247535,0.));
#478=CARTESIAN_POINT('',(-45.9481669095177,16.9194711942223,0.));
#479=CARTESIAN_POINT('',(-44.217955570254,17.6689942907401,0.));
#480=CARTESIAN_POINT('',(-43.0502715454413,18.1392862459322,0.));
#481=CARTESIAN_POINT('',(-40.6940886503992,19.0263222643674,0.));
#482=CARTESIAN_POINT('',(-39.5055771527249,19.4430324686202,0.));
#483=CARTESIAN_POINT('',(-37.1137000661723,20.226840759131,0.));
#484=CARTESIAN_POINT('',(-35.9103508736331,20.5939890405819,0.));
#485=CARTESIAN_POINT('',(-33.4900525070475,21.2831450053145,0.));
#486=CARTESIAN_POINT('',(-32.2730954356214,21.6051248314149,0.));
#487=CARTESIAN_POINT('',(-29.8287700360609,22.2065938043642,0.));
#488=CARTESIAN_POINT('',(-28.6014017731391,22.4860832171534,0.));
#489=CARTESIAN_POINT('',(-26.1440203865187,23.0038685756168,0.));
#490=CARTESIAN_POINT('',(-24.9140463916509,23.2423508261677,0.));
#491=CARTESIAN_POINT('',(-22.4522037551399,23.6804649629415,0.));
#492=CARTESIAN_POINT('',(-21.2203615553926,23.8802458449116,0.));
#493=CARTESIAN_POINT('',(-18.7548847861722,24.2432316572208,0.));
#494=CARTESIAN_POINT('',(-17.521265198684,24.4065386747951,0.));
#495=CARTESIAN_POINT('',(-15.05230639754,24.6981945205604,0.));
#496=CARTESIAN_POINT('',(-13.8169750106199,24.8266097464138,0.));
#497=CARTESIAN_POINT('',(-11.3446337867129,25.0494324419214,0.));
#498=CARTESIAN_POINT('',(-10.1076273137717,25.143877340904,0.));
#499=CARTESIAN_POINT('',(-7.63198732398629,25.2998069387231,0.));
#500=CARTESIAN_POINT('',(-6.39335454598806,25.3613033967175,0.));
#501=CARTESIAN_POINT('',(-3.9144668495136,25.4515543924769,0.));
#502=CARTESIAN_POINT('',(-2.67421151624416,25.480297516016,0.));
#503=CARTESIAN_POINT('',(-0.192085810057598,25.5052866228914,0.));
#504=CARTESIAN_POINT('',(1.04978490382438,25.5014988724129,0.));
#505=CARTESIAN_POINT('',(2.29138758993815,25.4815579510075,0.));
#506=B_SPLINE_CURVE_WITH_KNOTS('',3,(#328,#329,#330,#331,#332,#333,#334,#335,#336,#337,#338,
#339,#340,#341,#342,#343,#344,#345,#346,#347,#348,#349,#350,#351,#352,#353,#354,#355,#356,#357,
#358,#359,#360,#361,#362,#363,#364,#365,#366,#367,#368,#369,#370,#371,#372,#373,#374,#375,#376,
#377,#378,#379,#380,#381,#382,#383,#384,#385,#386,#387,#388,#389,#390,#391,#392,#393,#394,#395,
#396,#397,#398,#399,#400,#401,#402,#403,#404,#405,#406,#407,#408,#409,#410,#411,#412,#413,#414,
#415,#416,#417,#418,#419,#420,#421,#422,#423,#424,#425,#426,#427,#428,#429,#430,#431,#432,#433,
#434,#435,#436,#437,#438,#439,#440,#441,#442,#443,#444,#445,#446,#447,#448,#449,#450,#451,#452,
#453,#454,#455,#456,#457,#458,#459,#460,#461,#462,#463,#464,#465,#466,#467,#468,#469,#470,#471,
#472,#473,#474,#475,#476,#477,#478,#479,#480,#481,#482,#483,#484,#485,#486,#487,#488,#489,#490,
#491,#492,#493,#494,#495,#496,#497,#498,#499,#500,#501,#502,#503,#504,#505),.UNSPECIFIED.,.F.,
.F.,(4,2,2,2,2,2,2,2,2,2,2,2,2,2,2,2,2,2,2,2,2,2,2,2,2,2,2,2,2,2,2,2,2,2,2,2,2,2,2,2,2,2,2,2,2,
2,2,2,2,2,2,2,2,2,2,2,2,2,2,2,2,2,2,2,2,2,2,2,2,2,2,2,2,2,2,2,2,2,2,2,2,2,2,2,2,2,2,2,4),(0.,
3.74868510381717,7.50891058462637,11.2641659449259,15.0084909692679,18.7445126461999,
22.4749820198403,26.2028325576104,29.9313511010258,33.6643432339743,37.4064955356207,
41.1639596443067,44.9370275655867,48.6983920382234,50.5748779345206,52.4500159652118,
54.3253243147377,56.2027578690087,58.0848723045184,59.975576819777,61.8713040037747,
62.8163928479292,63.7598276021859,64.7023191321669,65.644794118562,66.5884211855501,
67.5348000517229,68.4858813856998,69.4372015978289,69.911811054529,70.3856186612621,
70.8588327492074,71.3323423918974,71.8070141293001,72.2844251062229,72.7626356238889,
73.2388903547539,73.4760998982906,73.7129234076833,73.9495793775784,74.1863126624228,
74.423394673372,74.6611232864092,74.8998224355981,75.1398413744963,75.3807176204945,
75.621292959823,75.8613853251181,76.1007980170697,76.3393138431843,76.5770239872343,
76.8143086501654,77.0514134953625,77.5258880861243,78.0025085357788,78.4804417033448,
78.9571285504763,79.4311979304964,79.9034888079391,80.3747357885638,80.8454960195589,
81.7872096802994,82.7318819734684,83.6805181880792,84.6301100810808,85.5781974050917,
86.5254885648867,87.4729931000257,88.4214959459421,90.3183375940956,92.2060878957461,
94.0874985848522,95.9657756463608,97.8434701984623,99.7224110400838,101.604032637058,
105.378877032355,109.156095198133,112.929458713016,116.705139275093,120.480796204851,
124.238818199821,127.982071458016,131.714712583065,135.440200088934,139.161570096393,
142.881611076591,146.602948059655,150.328144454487),.UNSPECIFIED.);
#507=CARTESIAN_POINT('',(2.29140733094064,-25.4815575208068,0.));
#508=VERTEX_POINT('',#507);
#509=EDGE_CURVE('E187',#325,#508,#506,.F.);
#510=ORIENTED_EDGE('',*,*,#509,.T.);
#511=CARTESIAN_POINT('',(2.05775386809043,-10.9834401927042,0.));
#512=DIRECTION('',(0.,0.,1.));
#513=DIRECTION('',(1.,0.,0.));
#514=AXIS2_PLACEMENT_3D('',#511,#512,#513);
#515=CIRCLE('',#514,14.5000000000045);
#516=CARTESIAN_POINT('',(15.9859201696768,-6.95154442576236,0.));
#517=VERTEX_POINT('',#516);
#518=EDGE_CURVE('E296',#508,#517,#515,.T.);
#519=ORIENTED_EDGE('',*,*,#518,.T.);
#520=CARTESIAN_POINT('',(40.,0.,0.));
#521=DIRECTION('',(0.,0.,-1.));
#522=DIRECTION('',(1.,0.,0.));
#523=AXIS2_PLACEMENT_3D('',#520,#521,#522);
#524=CIRCLE('',#523,25.0000000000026);
#525=EDGE_CURVE('E148',#517,#323,#524,.T.);
#526=ORIENTED_EDGE('',*,*,#525,.T.);
#527=EDGE_LOOP('',(#327,#510,#519,#526));
#528=FACE_BOUND('',#527,.T.);
#529=ORIENTED_EDGE('',*,*,#272,.F.);
#530=EDGE_LOOP('',(#529));
#531=FACE_BOUND('',#530,.T.);
#532=ADVANCED_FACE('F211',(#316,#528,#531),#281,.F.);
#533=CARTESIAN_POINT('',(40.,0.,20.));
#534=DIRECTION('',(0.,0.,-1.));
#535=DIRECTION('',(-1.,0.,0.));
#536=AXIS2_PLACEMENT_3D('',#533,#534,#535);
#537=CYLINDRICAL_SURFACE('',#536,17.5);
#538=CARTESIAN_POINT('',(40.,0.,20.));
#539=DIRECTION('',(0.,0.,1.));
#540=DIRECTION('',(1.,0.,0.));
#541=AXIS2_PLACEMENT_3D('',#538,#539,#540);
#542=CIRCLE('',#541,17.5);
#543=CARTESIAN_POINT('',(57.5,0.,20.));
#544=VERTEX_POINT('',#543);
#545=EDGE_CURVE('E193',#544,#544,#542,.T.);
#546=ORIENTED_EDGE('',*,*,#545,.F.);
#547=EDGE_LOOP('',(#546));
#548=FACE_BOUND('',#547,.T.);
#549=ORIENTED_EDGE('',*,*,#254,.T.);
#550=EDGE_LOOP('',(#549));
#551=FACE_BOUND('',#550,.T.);
#552=ADVANCED_FACE('F224',(#548,#551),#537,.T.);
#553=CARTESIAN_POINT('',(40.,0.,20.));
#554=DIRECTION('',(0.,0.,1.));
#555=DIRECTION('',(1.,0.,0.));
#556=AXIS2_PLACEMENT_3D('',#553,#554,#555);
#557=PLANE('',#556);
#558=CARTESIAN_POINT('',(40.,0.,20.));
#559=DIRECTION('',(0.,0.,1.));
#560=DIRECTION('',(1.,0.,0.));
#561=AXIS2_PLACEMENT_3D('',#558,#559,#560);
#562=CIRCLE('',#561,10.);
#563=CARTESIAN_POINT('',(38.,9.79795897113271,20.));
#564=VERTEX_POINT('',#563);
#565=CARTESIAN_POINT('',(42.,9.79795897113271,20.));
#566=VERTEX_POINT('',#565);
#567=EDGE_CURVE('E69',#564,#566,#562,.T.);
#568=ORIENTED_EDGE('',*,*,#567,.F.);
#569=DIRECTION('',(0.,-1.,0.));
#570=VECTOR('',#569,1.);
#571=CARTESIAN_POINT('',(38.,9.79795897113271,20.));
#572=LINE('',#571,#570);
#573=CARTESIAN_POINT('',(38.,12.2979589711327,20.));
#574=VERTEX_POINT('',#573);
#575=EDGE_CURVE('E130',#574,#564,#572,.T.);
#576=ORIENTED_EDGE('',*,*,#575,.F.);
#577=DIRECTION('',(-1.,0.,0.));
#578=VECTOR('',#577,1.);
#579=CARTESIAN_POINT('',(38.,12.2979589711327,20.));
#580=LINE('',#579,#578);
#581=CARTESIAN_POINT('',(42.,12.2979589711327,20.));
#582=VERTEX_POINT('',#581);
#583=EDGE_CURVE('E111',#582,#574,#580,.T.);
#584=ORIENTED_EDGE('',*,*,#583,.F.);
#585=DIRECTION('',(0.,1.,0.));
#586=VECTOR('',#585,1.);
#587=CARTESIAN_POINT('',(42.,12.2979589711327,20.));
#588=LINE('',#587,#586);
#589=EDGE_CURVE('E119',#566,#582,#588,.T.);
#590=ORIENTED_EDGE('',*,*,#589,.F.);
#591=EDGE_LOOP('',(#568,#576,#584,#590));
#592=FACE_BOUND('',#591,.T.);
#593=ORIENTED_EDGE('',*,*,#545,.T.);
#594=EDGE_LOOP('',(#593));
#595=FACE_BOUND('',#594,.T.);
#596=ADVANCED_FACE('F121',(#592,#595),#557,.T.);
#597=CARTESIAN_POINT('',(-64.,0.,0.));
#598=CARTESIAN_POINT('',(-64.,-0.778637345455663,0.));
#599=CARTESIAN_POINT('',(-63.8590691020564,-1.53017141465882,0.));
#600=CARTESIAN_POINT('',(-63.4971637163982,-2.62852721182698,0.));
#601=CARTESIAN_POINT('',(-63.3514110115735,-2.98902067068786,0.));
#602=CARTESIAN_POINT('',(-63.0270732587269,-3.68461727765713,0.));
#603=CARTESIAN_POINT('',(-62.8476125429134,-4.02238124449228,0.));
#604=CARTESIAN_POINT('',(-62.2676377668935,-5.01153722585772,0.));
#605=CARTESIAN_POINT('',(-61.8244953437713,-5.64103629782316,0.));
#606=CARTESIAN_POINT('',(-60.8650574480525,-6.84514237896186,0.));
#607=CARTESIAN_POINT('',(-60.3539398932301,-7.41337525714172,0.));
#608=CARTESIAN_POINT('',(-58.7511249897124,-9.04325451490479,0.));
#609=CARTESIAN_POINT('',(-57.5909447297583,-10.031136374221,0.));
#610=CARTESIAN_POINT('',(-55.7580257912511,-11.413165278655,0.));
#611=CARTESIAN_POINT('',(-55.1306220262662,-11.8569621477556,0.));
#612=CARTESIAN_POINT('',(-53.8614741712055,-12.7062726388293,0.));
#613=CARTESIAN_POINT('',(-53.2180319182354,-13.113090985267,0.));
#614=CARTESIAN_POINT('',(-51.2648212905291,-14.2875196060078,0.));
#615=CARTESIAN_POINT('',(-49.9323550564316,-15.0094775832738,0.));
#616=CARTESIAN_POINT('',(-47.2193890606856,-16.3567835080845,0.));
#617=CARTESIAN_POINT('',(-45.8387722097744,-16.9818959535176,0.));
#618=CARTESIAN_POINT('',(-43.0368500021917,-18.1502838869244,0.));
#619=CARTESIAN_POINT('',(-41.6154949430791,-18.6934594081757,0.));
#620=CARTESIAN_POINT('',(-38.7369036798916,-19.7076425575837,0.));
#621=CARTESIAN_POINT('',(-37.2891432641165,-20.1752648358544,0.));
#622=CARTESIAN_POINT('',(-32.9300236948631,-21.4729085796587,0.));
#623=CARTESIAN_POINT('',(-29.9999896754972,-22.1996484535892,0.));
#624=CARTESIAN_POINT('',(-24.1004676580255,-23.4252488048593,0.));
#625=CARTESIAN_POINT('',(-21.1308888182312,-23.9235845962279,0.));
#626=CARTESIAN_POINT('',(-15.1563094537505,-24.715666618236,0.));
#627=CARTESIAN_POINT('',(-12.1512761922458,-25.0092237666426,0.));
#628=CARTESIAN_POINT('',(-7.61839700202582,-25.3032618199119,0.));
#629=CARTESIAN_POINT('',(-6.10319937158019,-25.3767971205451,0.));
#630=CARTESIAN_POINT('',(-3.06436015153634,-25.4750968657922,0.));
#631=CARTESIAN_POINT('',(-1.54631446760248,-25.4996572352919,0.));
#632=CARTESIAN_POINT('',(2.99720012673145,-25.5006748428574,0.));
#633=CARTESIAN_POINT('',(6.01495560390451,-25.4048837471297,0.));
#634=CARTESIAN_POINT('',(12.0278615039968,-25.0195349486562,0.));
#635=CARTESIAN_POINT('',(15.0230191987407,-24.7300395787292,0.));
#636=CARTESIAN_POINT('',(20.9893547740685,-23.9454980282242,0.));
#637=CARTESIAN_POINT('',(23.9605579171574,-23.4506683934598,0.));
#638=CARTESIAN_POINT('',(28.3970555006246,-22.5343547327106,0.));
#639=CARTESIAN_POINT('',(29.8724881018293,-22.1997732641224,0.));
#640=CARTESIAN_POINT('',(32.8159032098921,-21.4667494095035,0.));
#641=CARTESIAN_POINT('',(34.286373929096,-21.0675872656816,0.));
#642=CARTESIAN_POINT('',(38.6679801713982,-19.7677804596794,0.));
#643=CARTESIAN_POINT('',(41.5321630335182,-18.7722823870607,0.));
#644=CARTESIAN_POINT('',(45.7202860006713,-17.0338653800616,0.));
#645=CARTESIAN_POINT('',(47.0981576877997,-16.4132047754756,0.));
#646=CARTESIAN_POINT('',(49.8104837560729,-15.0734602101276,0.));
#647=CARTESIAN_POINT('',(51.1450506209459,-14.354631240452,0.));
#648=CARTESIAN_POINT('',(53.1056257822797,-13.1828205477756,0.));
#649=CARTESIAN_POINT('',(53.752227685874,-12.7765227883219,0.));
#650=CARTESIAN_POINT('',(55.0292417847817,-11.9272265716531,0.));
#651=CARTESIAN_POINT('',(55.6565474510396,-11.4862154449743,0.));
#652=CARTESIAN_POINT('',(57.4901717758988,-10.1132523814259,0.));
#653=CARTESIAN_POINT('',(58.6535978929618,-9.13088273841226,0.));
#654=CARTESIAN_POINT('',(60.2666678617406,-7.50718978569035,0.));
#655=CARTESIAN_POINT('',(60.7822850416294,-6.94044683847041,0.));
#656=CARTESIAN_POINT('',(61.7522513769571,-5.73900220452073,0.));
#657=CARTESIAN_POINT('',(62.1996207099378,-5.11347520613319,0.));
#658=CARTESIAN_POINT('',(62.7917707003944,-4.12315096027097,0.));
#659=CARTESIAN_POINT('',(62.9765601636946,-3.7827808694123,0.));
#660=CARTESIAN_POINT('',(63.3091638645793,-3.08727762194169,0.));
#661=CARTESIAN_POINT('',(63.4563713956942,-2.73377949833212,0.));
#662=CARTESIAN_POINT('',(63.7045059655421,-2.0128549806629,0.));
#663=CARTESIAN_POINT('',(63.8054476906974,-1.64543300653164,0.));
#664=CARTESIAN_POINT('',(63.9133815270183,-1.08121496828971,0.));
#665=CARTESIAN_POINT('',(63.9420801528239,-0.890951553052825,0.));
#666=CARTESIAN_POINT('',(63.9831959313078,-0.505524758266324,0.));
#667=CARTESIAN_POINT('',(63.9954558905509,-0.310463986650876,0.));
#668=CARTESIAN_POINT('',(64.005909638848,0.268736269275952,0.));
#669=CARTESIAN_POINT('',(63.9781998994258,0.651343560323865,0.));
#670=CARTESIAN_POINT('',(63.8595638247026,1.41013016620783,0.));
#671=CARTESIAN_POINT('',(63.7678689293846,1.78910896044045,0.));
#672=CARTESIAN_POINT('',(63.4187237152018,2.89565090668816,0.));
#673=CARTESIAN_POINT('',(63.0934089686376,3.58973080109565,0.));
#674=CARTESIAN_POINT('',(62.5181219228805,4.58970353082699,0.));
#675=CARTESIAN_POINT('',(62.3104537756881,4.91709438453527,0.));
#676=CARTESIAN_POINT('',(61.8741736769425,5.55305326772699,0.));
#677=CARTESIAN_POINT('',(61.6457441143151,5.86160089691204,0.));
#678=CARTESIAN_POINT('',(60.9348411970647,6.76376467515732,0.));
#679=CARTESIAN_POINT('',(60.4270171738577,7.3341433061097,0.));
#680=CARTESIAN_POINT('',(59.3602946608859,8.42808350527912,0.));
#681=CARTESIAN_POINT('',(58.801205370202,8.95147017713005,0.));
#682=CARTESIAN_POINT('',(57.6411259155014,9.95983536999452,0.));
#683=CARTESIAN_POINT('',(57.0422554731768,10.4426982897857,0.));
#684=CARTESIAN_POINT('',(55.2145859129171,11.8269038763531,0.));
#685=CARTESIAN_POINT('',(53.948554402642,12.6704180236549,0.));
#686=CARTESIAN_POINT('',(51.3468543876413,14.2414124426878,0.));
#687=CARTESIAN_POINT('',(50.0108386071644,14.9683140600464,0.));
#688=CARTESIAN_POINT('',(47.9643155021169,15.9878510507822,0.));
#689=CARTESIAN_POINT('',(47.2749972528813,16.3157930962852,0.));
#690=CARTESIAN_POINT('',(45.8832293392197,16.9497967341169,0.));
#691=CARTESIAN_POINT('',(45.1807948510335,17.2557954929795,0.));
#692=CARTESIAN_POINT('',(41.6594608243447,18.7264803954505,0.));
#693=CARTESIAN_POINT('',(38.7962076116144,19.7245117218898,0.));
#694=CARTESIAN_POINT('',(33.0007177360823,21.4539417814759,0.));
#695=CARTESIAN_POINT('',(30.0681241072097,22.1839607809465,0.));
#696=CARTESIAN_POINT('',(24.1443711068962,23.4176323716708,0.));
#697=CARTESIAN_POINT('',(21.1530971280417,23.9208419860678,0.));
#698=CARTESIAN_POINT('',(16.6260976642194,24.5207076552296,0.));
#699=CARTESIAN_POINT('',(15.110510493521,24.6945702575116,0.));
#700=CARTESIAN_POINT('',(12.0872544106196,24.990031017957,0.));
#701=CARTESIAN_POINT('',(10.5769048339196,25.1120083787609,0.));
#702=CARTESIAN_POINT('',(6.0495430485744,25.4036717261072,0.));
#703=CARTESIAN_POINT('',(3.03620169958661,25.4994129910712,0.));
#704=CARTESIAN_POINT('',(-2.98103319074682,25.5005816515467,0.));
#705=CARTESIAN_POINT('',(-5.98492589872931,25.4059922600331,0.));
#706=CARTESIAN_POINT('',(-11.9831001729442,25.0232094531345,0.));
#707=CARTESIAN_POINT('',(-14.9773860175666,24.7351022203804,0.));
#708=CARTESIAN_POINT('',(-20.955630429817,23.9508581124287,0.));
#709=CARTESIAN_POINT('',(-23.9396019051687,23.4549812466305,0.));
#710=CARTESIAN_POINT('',(-28.4066832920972,22.5323739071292,0.));
#711=CARTESIAN_POINT('',(-29.8967809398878,22.1942151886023,0.));
#712=CARTESIAN_POINT('',(-32.8578406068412,21.4558024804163,0.));
#713=CARTESIAN_POINT('',(-34.3289954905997,21.0556597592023,0.));
#714=CARTESIAN_POINT('',(-37.2507280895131,20.1874717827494,0.));
#715=CARTESIAN_POINT('',(-38.701317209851,19.7194641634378,0.));
#716=CARTESIAN_POINT('',(-41.5793010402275,18.7069097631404,0.));
#717=CARTESIAN_POINT('',(-43.0087867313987,18.1614358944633,0.));
#718=CARTESIAN_POINT('',(-45.8208526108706,16.9899096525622,0.));
#719=CARTESIAN_POINT('',(-47.2053176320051,16.3634238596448,0.));
#720=CARTESIAN_POINT('',(-49.9233260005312,15.0143063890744,0.));
#721=CARTESIAN_POINT('',(-51.2569869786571,14.2918968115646,0.));
#722=CARTESIAN_POINT('',(-53.860708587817,12.7269930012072,0.));
#723=CARTESIAN_POINT('',(-55.1318070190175,11.8846212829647,0.));
#724=CARTESIAN_POINT('',(-57.5838787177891,10.0371733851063,0.));
#725=CARTESIAN_POINT('',(-58.7496770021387,9.04538050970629,0.));
#726=CARTESIAN_POINT('',(-60.3625882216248,7.40425170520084,0.));
#727=CARTESIAN_POINT('',(-60.8763650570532,6.8315852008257,0.));
#728=CARTESIAN_POINT('',(-61.825648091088,5.63894720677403,0.));
#729=CARTESIAN_POINT('',(-62.2636596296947,5.01732045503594,0.));
#730=CARTESIAN_POINT('',(-62.8428025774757,4.0310767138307,0.));
#731=CARTESIAN_POINT('',(-63.0227349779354,3.69326743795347,0.));
#732=CARTESIAN_POINT('',(-63.3491402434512,2.99453159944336,0.));
#733=CARTESIAN_POINT('',(-63.4946721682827,2.63486681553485,0.));
#734=CARTESIAN_POINT('',(-63.7355029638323,1.90638021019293,0.));
#735=CARTESIAN_POINT('',(-63.8317472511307,1.53562276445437,0.));
#736=CARTESIAN_POINT('',(-63.9642606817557,0.777944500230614,0.));
#737=CARTESIAN_POINT('',(-64.,0.389318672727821,0.));
#738=CARTESIAN_POINT('',(-64.,0.,0.));
#739=B_SPLINE_CURVE_WITH_KNOTS('',3,(#597,#598,#599,#600,#601,#602,#603,#604,#605,#606,#607,
#608,#609,#610,#611,#612,#613,#614,#615,#616,#617,#618,#619,#620,#621,#622,#623,#624,#625,#626,
#627,#628,#629,#630,#631,#632,#633,#634,#635,#636,#637,#638,#639,#640,#641,#642,#643,#644,#645,
#646,#647,#648,#649,#650,#651,#652,#653,#654,#655,#656,#657,#658,#659,#660,#661,#662,#663,#664,
#665,#666,#667,#668,#669,#670,#671,#672,#673,#674,#675,#676,#677,#678,#679,#680,#681,#682,#683,
#684,#685,#686,#687,#688,#689,#690,#691,#692,#693,#694,#695,#696,#697,#698,#699,#700,#701,#702,
#703,#704,#705,#706,#707,#708,#709,#710,#711,#712,#713,#714,#715,#716,#717,#718,#719,#720,#721,
#722,#723,#724,#725,#726,#727,#728,#729,#730,#731,#732,#733,#734,#735,#736,#737,#738),
.UNSPECIFIED.,.T.,.F.,(4,2,2,2,2,2,2,2,2,2,2,2,2,2,2,2,2,2,2,2,2,2,2,2,2,2,2,2,2,2,2,2,2,2,2,2,
2,2,2,2,2,2,2,2,2,2,2,2,2,2,2,2,2,2,2,2,2,2,2,2,2,2,2,2,2,2,2,2,2,2,4),(0.,0.00781250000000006,
0.0117187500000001,0.0156250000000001,0.0234375,0.03125,0.046875,0.0546875,0.0625,0.078125,
0.0937500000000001,0.109375,0.125,0.15625,0.187500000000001,0.218750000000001,0.234375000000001,
0.250000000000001,0.281250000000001,0.312500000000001,0.343750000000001,0.359375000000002,
0.375000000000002,0.406250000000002,0.421875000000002,0.437500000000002,0.445312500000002,
0.453125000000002,0.468750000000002,0.476562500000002,0.484375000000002,0.488281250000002,
0.492187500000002,0.496093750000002,0.498046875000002,0.500000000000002,0.503906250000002,
0.507812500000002,0.515625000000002,0.519531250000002,0.523437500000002,0.531250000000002,
0.539062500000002,0.546875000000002,0.562500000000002,0.578125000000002,0.585937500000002,
0.593750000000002,0.625000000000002,0.656250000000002,0.687500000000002,0.703125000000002,
0.718750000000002,0.750000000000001,0.781250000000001,0.812500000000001,0.843750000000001,
0.859375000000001,0.875000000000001,0.890625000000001,0.906250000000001,0.921875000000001,
0.937500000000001,0.953125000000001,0.96875,0.9765625,0.984375,0.98828125,0.9921875,0.99609375,
1.),.UNSPECIFIED.);
#740=DIRECTION('',(0.,0.,1.));
#741=VECTOR('',#740,1.);
#742=SURFACE_OF_LINEAR_EXTRUSION('',#739,#741);
#743=ORIENTED_EDGE('',*,*,#207,.T.);
#744=DIRECTION('',(0.,0.,1.));
#745=VECTOR('',#744,1.);
#746=CARTESIAN_POINT('',(2.29140733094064,-25.4815575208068,0.));
#747=LINE('',#746,#745);
#748=EDGE_CURVE('E295',#508,#206,#747,.T.);
#749=ORIENTED_EDGE('',*,*,#748,.F.);
#750=ORIENTED_EDGE('',*,*,#509,.F.);
#751=DIRECTION('',(0.,0.,1.));
#752=VECTOR('',#751,1.);
#753=CARTESIAN_POINT('',(2.29138758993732,25.4815579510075,0.));
#754=LINE('',#753,#752);
#755=EDGE_CURVE('E197',#325,#204,#754,.T.);
#756=ORIENTED_EDGE('',*,*,#755,.T.);
#757=EDGE_LOOP('',(#743,#749,#750,#756));
#758=FACE_BOUND('',#757,.T.);
#759=ADVANCED_FACE('F157',(#758),#742,.F.);
#760=CARTESIAN_POINT('',(2.05775390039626,10.9834403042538,0.));
#761=DIRECTION('',(0.,0.,1.));
#762=DIRECTION('',(1.,0.,0.));
#763=AXIS2_PLACEMENT_3D('',#760,#761,#762);
#764=CYLINDRICAL_SURFACE('',#763,14.5);
#765=ORIENTED_EDGE('',*,*,#216,.T.);
#766=ORIENTED_EDGE('',*,*,#755,.F.);
#767=ORIENTED_EDGE('',*,*,#326,.F.);
#768=DIRECTION('',(0.,0.,1.));
#769=VECTOR('',#768,1.);
#770=CARTESIAN_POINT('',(15.9859201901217,6.95154449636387,0.));
#771=LINE('',#770,#769);
#772=EDGE_CURVE('E284',#323,#215,#771,.T.);
#773=ORIENTED_EDGE('',*,*,#772,.T.);
#774=EDGE_LOOP('',(#765,#766,#767,#773));
#775=FACE_BOUND('',#774,.T.);
#776=ADVANCED_FACE('F163',(#775),#764,.F.);
#777=CARTESIAN_POINT('',(40.,0.,0.));
#778=DIRECTION('',(0.,0.,1.));
#779=DIRECTION('',(1.,0.,0.));
#780=AXIS2_PLACEMENT_3D('',#777,#778,#779);
#781=CYLINDRICAL_SURFACE('',#780,25.0000000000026);
#782=ORIENTED_EDGE('',*,*,#225,.T.);
#783=ORIENTED_EDGE('',*,*,#772,.F.);
#784=ORIENTED_EDGE('',*,*,#525,.F.);
#785=DIRECTION('',(0.,0.,1.));
#786=VECTOR('',#785,1.);
#787=CARTESIAN_POINT('',(15.9859201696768,-6.95154442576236,0.));
#788=LINE('',#787,#786);
#789=EDGE_CURVE('E290',#517,#224,#788,.T.);
#790=ORIENTED_EDGE('',*,*,#789,.T.);
#791=EDGE_LOOP('',(#782,#783,#784,#790));
#792=FACE_BOUND('',#791,.T.);
#793=ADVANCED_FACE('F273',(#792),#781,.T.);
#794=CARTESIAN_POINT('',(2.05775386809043,-10.9834401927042,0.));
#795=DIRECTION('',(0.,0.,1.));
#796=DIRECTION('',(1.,0.,0.));
#797=AXIS2_PLACEMENT_3D('',#794,#795,#796);
#798=CYLINDRICAL_SURFACE('',#797,14.5000000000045);
#799=ORIENTED_EDGE('',*,*,#232,.T.);
#800=ORIENTED_EDGE('',*,*,#789,.F.);
#801=ORIENTED_EDGE('',*,*,#518,.F.);
#802=ORIENTED_EDGE('',*,*,#748,.T.);
#803=EDGE_LOOP('',(#799,#800,#801,#802));
#804=FACE_BOUND('',#803,.T.);
#805=ADVANCED_FACE('F161',(#804),#798,.F.);
#806=CARTESIAN_POINT('',(40.,0.,-0.00999999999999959));
#807=DIRECTION('',(0.,0.,1.));
#808=DIRECTION('',(1.,0.,0.));
#809=AXIS2_PLACEMENT_3D('',#806,#807,#808);
#810=CYLINDRICAL_SURFACE('',#809,10.);
#811=DIRECTION('',(0.,0.,1.));
#812=VECTOR('',#811,1.);
#813=CARTESIAN_POINT('',(38.,9.79795897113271,-0.00999999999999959));
#814=LINE('',#813,#812);
#815=EDGE_CURVE('E131',#289,#564,#814,.T.);
#816=ORIENTED_EDGE('',*,*,#815,.T.);
#817=ORIENTED_EDGE('',*,*,#567,.T.);
#818=DIRECTION('',(0.,0.,1.));
#819=VECTOR('',#818,1.);
#820=CARTESIAN_POINT('',(42.,9.79795897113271,-0.00999999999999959));
#821=LINE('',#820,#819);
#822=EDGE_CURVE('E120',#298,#566,#821,.T.);
#823=ORIENTED_EDGE('',*,*,#822,.F.);
#824=ORIENTED_EDGE('',*,*,#299,.F.);
#825=EDGE_LOOP('',(#816,#817,#823,#824));
#826=FACE_BOUND('',#825,.T.);
#827=ADVANCED_FACE('F246',(#826),#810,.F.);
#828=CARTESIAN_POINT('',(38.,9.79795897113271,-0.00999999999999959));
#829=DIRECTION('',(-1.,0.,0.));
#830=DIRECTION('',(0.,0.,1.));
#831=AXIS2_PLACEMENT_3D('',#828,#829,#830);
#832=PLANE('',#831);
#833=DIRECTION('',(0.,0.,1.));
#834=VECTOR('',#833,1.);
#835=CARTESIAN_POINT('',(38.,12.2979589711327,-0.00999999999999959));
#836=LINE('',#835,#834);
#837=EDGE_CURVE('E116',#287,#574,#836,.T.);
#838=ORIENTED_EDGE('',*,*,#837,.T.);
#839=ORIENTED_EDGE('',*,*,#575,.T.);
#840=ORIENTED_EDGE('',*,*,#815,.F.);
#841=ORIENTED_EDGE('',*,*,#290,.F.);
#842=EDGE_LOOP('',(#838,#839,#840,#841));
#843=FACE_BOUND('',#842,.T.);
#844=ADVANCED_FACE('F249',(#843),#832,.F.);
#845=CARTESIAN_POINT('',(38.,12.2979589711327,-0.00999999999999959));
#846=DIRECTION('',(0.,1.,0.));
#847=DIRECTION('',(0.,0.,1.));
#848=AXIS2_PLACEMENT_3D('',#845,#846,#847);
#849=PLANE('',#848);
#850=DIRECTION('',(0.,0.,1.));
#851=VECTOR('',#850,1.);
#852=CARTESIAN_POINT('',(42.,12.2979589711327,-0.00999999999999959));
#853=LINE('',#852,#851);
#854=EDGE_CURVE('E59',#306,#582,#853,.T.);
#855=ORIENTED_EDGE('',*,*,#854,.T.);
#856=ORIENTED_EDGE('',*,*,#583,.T.);
#857=ORIENTED_EDGE('',*,*,#837,.F.);
#858=ORIENTED_EDGE('',*,*,#313,.F.);
#859=EDGE_LOOP('',(#855,#856,#857,#858));
#860=FACE_BOUND('',#859,.T.);
#861=ADVANCED_FACE('F108',(#860),#849,.F.);
#862=CARTESIAN_POINT('',(42.,12.2979589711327,-0.00999999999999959));
#863=DIRECTION('',(1.,0.,0.));
#864=DIRECTION('',(0.,0.,-1.));
#865=AXIS2_PLACEMENT_3D('',#862,#863,#864);
#866=PLANE('',#865);
#867=ORIENTED_EDGE('',*,*,#822,.T.);
#868=ORIENTED_EDGE('',*,*,#589,.T.);
#869=ORIENTED_EDGE('',*,*,#854,.F.);
#870=ORIENTED_EDGE('',*,*,#307,.F.);
#871=EDGE_LOOP('',(#867,#868,#869,#870));
#872=FACE_BOUND('',#871,.T.);
#873=ADVANCED_FACE('F122',(#872),#866,.F.);
#874=CLOSED_SHELL('',(#258,#276,#532,#552,#596,#759,#776,#793,#805,#827,#844,#861,#873));
#875=MANIFOLD_SOLID_BREP('B2',#874);
#876=ADVANCED_BREP_SHAPE_REPRESENTATION('',(#18,#875),#14);
#877=SHAPE_DEFINITION_REPRESENTATION(#9,#876);
ENDSEC;
END-ISO-10303-21;
